VERSION 5.4 ;
NAMESCASESENSITIVE ON ;
BUSBITCHARS "[]" ;
DIVIDERCHAR "/" ;
UNITS
  DATABASE MICRONS 2000 ;
END UNITS
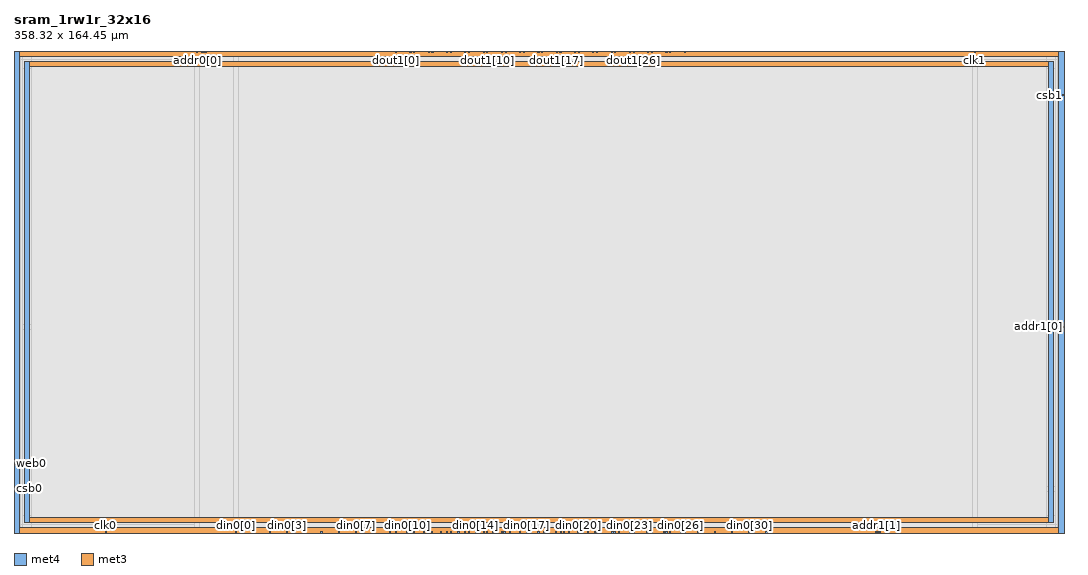
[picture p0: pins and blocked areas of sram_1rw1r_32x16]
MACRO sram_1rw1r_32x16
   CLASS BLOCK ;
   SIZE 358.32 BY 164.45 ;
   SYMMETRY X Y R90 ;
   PIN din0[0]
      DIRECTION INPUT ;
      PORT
         LAYER met4 ;
         RECT  75.56 0.0 75.94 0.38 ;
      END
   END din0[0]
   PIN din0[1]
      DIRECTION INPUT ;
      PORT
         LAYER met4 ;
         RECT  81.4 0.0 81.78 0.38 ;
      END
   END din0[1]
   PIN din0[2]
      DIRECTION INPUT ;
      PORT
         LAYER met4 ;
         RECT  87.24 0.0 87.62 0.38 ;
      END
   END din0[2]
   PIN din0[3]
      DIRECTION INPUT ;
      PORT
         LAYER met4 ;
         RECT  93.08 0.0 93.46 0.38 ;
      END
   END din0[3]
   PIN din0[4]
      DIRECTION INPUT ;
      PORT
         LAYER met4 ;
         RECT  98.92 0.0 99.3 0.38 ;
      END
   END din0[4]
   PIN din0[5]
      DIRECTION INPUT ;
      PORT
         LAYER met4 ;
         RECT  104.76 0.0 105.14 0.38 ;
      END
   END din0[5]
   PIN din0[6]
      DIRECTION INPUT ;
      PORT
         LAYER met4 ;
         RECT  110.6 0.0 110.98 0.38 ;
      END
   END din0[6]
   PIN din0[7]
      DIRECTION INPUT ;
      PORT
         LAYER met4 ;
         RECT  116.44 0.0 116.82 0.38 ;
      END
   END din0[7]
   PIN din0[8]
      DIRECTION INPUT ;
      PORT
         LAYER met4 ;
         RECT  122.28 0.0 122.66 0.38 ;
      END
   END din0[8]
   PIN din0[9]
      DIRECTION INPUT ;
      PORT
         LAYER met4 ;
         RECT  128.12 0.0 128.5 0.38 ;
      END
   END din0[9]
   PIN din0[10]
      DIRECTION INPUT ;
      PORT
         LAYER met4 ;
         RECT  133.96 0.0 134.34 0.38 ;
      END
   END din0[10]
   PIN din0[11]
      DIRECTION INPUT ;
      PORT
         LAYER met4 ;
         RECT  139.8 0.0 140.18 0.38 ;
      END
   END din0[11]
   PIN din0[12]
      DIRECTION INPUT ;
      PORT
         LAYER met4 ;
         RECT  145.64 0.0 146.02 0.38 ;
      END
   END din0[12]
   PIN din0[13]
      DIRECTION INPUT ;
      PORT
         LAYER met4 ;
         RECT  151.48 0.0 151.86 0.38 ;
      END
   END din0[13]
   PIN din0[14]
      DIRECTION INPUT ;
      PORT
         LAYER met4 ;
         RECT  157.32 0.0 157.7 0.38 ;
      END
   END din0[14]
   PIN din0[15]
      DIRECTION INPUT ;
      PORT
         LAYER met4 ;
         RECT  163.16 0.0 163.54 0.38 ;
      END
   END din0[15]
   PIN din0[16]
      DIRECTION INPUT ;
      PORT
         LAYER met4 ;
         RECT  169.0 0.0 169.38 0.38 ;
      END
   END din0[16]
   PIN din0[17]
      DIRECTION INPUT ;
      PORT
         LAYER met4 ;
         RECT  174.84 0.0 175.22 0.38 ;
      END
   END din0[17]
   PIN din0[18]
      DIRECTION INPUT ;
      PORT
         LAYER met4 ;
         RECT  180.68 0.0 181.06 0.38 ;
      END
   END din0[18]
   PIN din0[19]
      DIRECTION INPUT ;
      PORT
         LAYER met4 ;
         RECT  186.52 0.0 186.9 0.38 ;
      END
   END din0[19]
   PIN din0[20]
      DIRECTION INPUT ;
      PORT
         LAYER met4 ;
         RECT  192.36 0.0 192.74 0.38 ;
      END
   END din0[20]
   PIN din0[21]
      DIRECTION INPUT ;
      PORT
         LAYER met4 ;
         RECT  198.2 0.0 198.58 0.38 ;
      END
   END din0[21]
   PIN din0[22]
      DIRECTION INPUT ;
      PORT
         LAYER met4 ;
         RECT  204.04 0.0 204.42 0.38 ;
      END
   END din0[22]
   PIN din0[23]
      DIRECTION INPUT ;
      PORT
         LAYER met4 ;
         RECT  209.88 0.0 210.26 0.38 ;
      END
   END din0[23]
   PIN din0[24]
      DIRECTION INPUT ;
      PORT
         LAYER met4 ;
         RECT  215.72 0.0 216.1 0.38 ;
      END
   END din0[24]
   PIN din0[25]
      DIRECTION INPUT ;
      PORT
         LAYER met4 ;
         RECT  221.56 0.0 221.94 0.38 ;
      END
   END din0[25]
   PIN din0[26]
      DIRECTION INPUT ;
      PORT
         LAYER met4 ;
         RECT  227.4 0.0 227.78 0.38 ;
      END
   END din0[26]
   PIN din0[27]
      DIRECTION INPUT ;
      PORT
         LAYER met4 ;
         RECT  233.24 0.0 233.62 0.38 ;
      END
   END din0[27]
   PIN din0[28]
      DIRECTION INPUT ;
      PORT
         LAYER met4 ;
         RECT  239.08 0.0 239.46 0.38 ;
      END
   END din0[28]
   PIN din0[29]
      DIRECTION INPUT ;
      PORT
         LAYER met4 ;
         RECT  244.92 0.0 245.3 0.38 ;
      END
   END din0[29]
   PIN din0[30]
      DIRECTION INPUT ;
      PORT
         LAYER met4 ;
         RECT  250.76 0.0 251.14 0.38 ;
      END
   END din0[30]
   PIN din0[31]
      DIRECTION INPUT ;
      PORT
         LAYER met4 ;
         RECT  256.6 0.0 256.98 0.38 ;
      END
   END din0[31]
   PIN addr0[0]
      DIRECTION INPUT ;
      PORT
         LAYER met4 ;
         RECT  62.34 164.07 62.72 164.45 ;
      END
   END addr0[0]
   PIN addr0[1]
      DIRECTION INPUT ;
      PORT
         LAYER met4 ;
         RECT  65.315 164.07 65.695 164.45 ;
      END
   END addr0[1]
   PIN addr0[2]
      DIRECTION INPUT ;
      PORT
         LAYER met4 ;
         RECT  64.625 164.07 65.005 164.45 ;
      END
   END addr0[2]
   PIN addr0[3]
      DIRECTION INPUT ;
      PORT
         LAYER met4 ;
         RECT  63.88 164.07 64.26 164.45 ;
      END
   END addr0[3]
   PIN addr1[0]
      DIRECTION INPUT ;
      PORT
         LAYER met3 ;
         RECT  357.94 70.215 358.32 70.595 ;
      END
   END addr1[0]
   PIN addr1[1]
      DIRECTION INPUT ;
      PORT
         LAYER met4 ;
         RECT  294.005 0.0 294.385 0.38 ;
      END
   END addr1[1]
   PIN addr1[2]
      DIRECTION INPUT ;
      PORT
         LAYER met4 ;
         RECT  294.695 0.0 295.075 0.38 ;
      END
   END addr1[2]
   PIN addr1[3]
      DIRECTION INPUT ;
      PORT
         LAYER met4 ;
         RECT  295.44 0.0 295.82 0.38 ;
      END
   END addr1[3]
   PIN csb0
      DIRECTION INPUT ;
      PORT
         LAYER met3 ;
         RECT  0.0 14.87 0.38 15.25 ;
      END
   END csb0
   PIN csb1
      DIRECTION INPUT ;
      PORT
         LAYER met3 ;
         RECT  357.94 149.2 358.32 149.58 ;
      END
   END csb1
   PIN web0
      DIRECTION INPUT ;
      PORT
         LAYER met3 ;
         RECT  0.0 23.37 0.38 23.75 ;
      END
   END web0
   PIN clk0
      DIRECTION INPUT ;
      PORT
         LAYER met4 ;
         RECT  31.1 0.0 31.48 0.38 ;
      END
   END clk0
   PIN clk1
      DIRECTION INPUT ;
      PORT
         LAYER met4 ;
         RECT  327.68 164.07 328.06 164.45 ;
      END
   END clk1
   PIN dout0[0]
      DIRECTION OUTPUT ;
      PORT
         LAYER met4 ;
         RECT  130.105 0.0 130.485 0.38 ;
      END
   END dout0[0]
   PIN dout0[1]
      DIRECTION OUTPUT ;
      PORT
         LAYER met4 ;
         RECT  135.135 0.0 135.515 0.38 ;
      END
   END dout0[1]
   PIN dout0[2]
      DIRECTION OUTPUT ;
      PORT
         LAYER met4 ;
         RECT  136.345 0.0 136.725 0.38 ;
      END
   END dout0[2]
   PIN dout0[3]
      DIRECTION OUTPUT ;
      PORT
         LAYER met4 ;
         RECT  141.375 0.0 141.755 0.38 ;
      END
   END dout0[3]
   PIN dout0[4]
      DIRECTION OUTPUT ;
      PORT
         LAYER met4 ;
         RECT  142.585 0.0 142.965 0.38 ;
      END
   END dout0[4]
   PIN dout0[5]
      DIRECTION OUTPUT ;
      PORT
         LAYER met4 ;
         RECT  147.615 0.0 147.995 0.38 ;
      END
   END dout0[5]
   PIN dout0[6]
      DIRECTION OUTPUT ;
      PORT
         LAYER met4 ;
         RECT  148.825 0.0 149.205 0.38 ;
      END
   END dout0[6]
   PIN dout0[7]
      DIRECTION OUTPUT ;
      PORT
         LAYER met4 ;
         RECT  153.855 0.0 154.235 0.38 ;
      END
   END dout0[7]
   PIN dout0[8]
      DIRECTION OUTPUT ;
      PORT
         LAYER met4 ;
         RECT  155.065 0.0 155.445 0.38 ;
      END
   END dout0[8]
   PIN dout0[9]
      DIRECTION OUTPUT ;
      PORT
         LAYER met4 ;
         RECT  160.095 0.0 160.475 0.38 ;
      END
   END dout0[9]
   PIN dout0[10]
      DIRECTION OUTPUT ;
      PORT
         LAYER met4 ;
         RECT  161.305 0.0 161.685 0.38 ;
      END
   END dout0[10]
   PIN dout0[11]
      DIRECTION OUTPUT ;
      PORT
         LAYER met4 ;
         RECT  166.335 0.0 166.715 0.38 ;
      END
   END dout0[11]
   PIN dout0[12]
      DIRECTION OUTPUT ;
      PORT
         LAYER met4 ;
         RECT  167.195 0.0 167.575 0.38 ;
      END
   END dout0[12]
   PIN dout0[13]
      DIRECTION OUTPUT ;
      PORT
         LAYER met4 ;
         RECT  172.575 0.0 172.955 0.38 ;
      END
   END dout0[13]
   PIN dout0[14]
      DIRECTION OUTPUT ;
      PORT
         LAYER met4 ;
         RECT  175.53 0.0 175.91 0.38 ;
      END
   END dout0[14]
   PIN dout0[15]
      DIRECTION OUTPUT ;
      PORT
         LAYER met4 ;
         RECT  178.815 0.0 179.195 0.38 ;
      END
   END dout0[15]
   PIN dout0[16]
      DIRECTION OUTPUT ;
      PORT
         LAYER met4 ;
         RECT  181.405 0.0 181.785 0.38 ;
      END
   END dout0[16]
   PIN dout0[17]
      DIRECTION OUTPUT ;
      PORT
         LAYER met4 ;
         RECT  184.715 0.0 185.095 0.38 ;
      END
   END dout0[17]
   PIN dout0[18]
      DIRECTION OUTPUT ;
      PORT
         LAYER met4 ;
         RECT  187.645 0.0 188.025 0.38 ;
      END
   END dout0[18]
   PIN dout0[19]
      DIRECTION OUTPUT ;
      PORT
         LAYER met4 ;
         RECT  189.355 0.0 189.735 0.38 ;
      END
   END dout0[19]
   PIN dout0[20]
      DIRECTION OUTPUT ;
      PORT
         LAYER met4 ;
         RECT  193.05 0.0 193.43 0.38 ;
      END
   END dout0[20]
   PIN dout0[21]
      DIRECTION OUTPUT ;
      PORT
         LAYER met4 ;
         RECT  195.595 0.0 195.975 0.38 ;
      END
   END dout0[21]
   PIN dout0[22]
      DIRECTION OUTPUT ;
      PORT
         LAYER met4 ;
         RECT  198.89 0.0 199.27 0.38 ;
      END
   END dout0[22]
   PIN dout0[23]
      DIRECTION OUTPUT ;
      PORT
         LAYER met4 ;
         RECT  204.73 0.0 205.11 0.38 ;
      END
   END dout0[23]
   PIN dout0[24]
      DIRECTION OUTPUT ;
      PORT
         LAYER met4 ;
         RECT  206.365 0.0 206.745 0.38 ;
      END
   END dout0[24]
   PIN dout0[25]
      DIRECTION OUTPUT ;
      PORT
         LAYER met4 ;
         RECT  210.57 0.0 210.95 0.38 ;
      END
   END dout0[25]
   PIN dout0[26]
      DIRECTION OUTPUT ;
      PORT
         LAYER met4 ;
         RECT  211.285 0.0 211.665 0.38 ;
      END
   END dout0[26]
   PIN dout0[27]
      DIRECTION OUTPUT ;
      PORT
         LAYER met4 ;
         RECT  216.41 0.0 216.79 0.38 ;
      END
   END dout0[27]
   PIN dout0[28]
      DIRECTION OUTPUT ;
      PORT
         LAYER met4 ;
         RECT  217.465 0.0 217.845 0.38 ;
      END
   END dout0[28]
   PIN dout0[29]
      DIRECTION OUTPUT ;
      PORT
         LAYER met4 ;
         RECT  222.495 0.0 222.875 0.38 ;
      END
   END dout0[29]
   PIN dout0[30]
      DIRECTION OUTPUT ;
      PORT
         LAYER met4 ;
         RECT  223.705 0.0 224.085 0.38 ;
      END
   END dout0[30]
   PIN dout0[31]
      DIRECTION OUTPUT ;
      PORT
         LAYER met4 ;
         RECT  228.735 0.0 229.115 0.38 ;
      END
   END dout0[31]
   PIN dout1[0]
      DIRECTION OUTPUT ;
      PORT
         LAYER met4 ;
         RECT  130.165 164.07 130.545 164.45 ;
      END
   END dout1[0]
   PIN dout1[1]
      DIRECTION OUTPUT ;
      PORT
         LAYER met4 ;
         RECT  135.135 164.07 135.515 164.45 ;
      END
   END dout1[1]
   PIN dout1[2]
      DIRECTION OUTPUT ;
      PORT
         LAYER met4 ;
         RECT  136.405 164.07 136.785 164.45 ;
      END
   END dout1[2]
   PIN dout1[3]
      DIRECTION OUTPUT ;
      PORT
         LAYER met4 ;
         RECT  141.375 164.07 141.755 164.45 ;
      END
   END dout1[3]
   PIN dout1[4]
      DIRECTION OUTPUT ;
      PORT
         LAYER met4 ;
         RECT  142.645 164.07 143.025 164.45 ;
      END
   END dout1[4]
   PIN dout1[5]
      DIRECTION OUTPUT ;
      PORT
         LAYER met4 ;
         RECT  147.615 164.07 147.995 164.45 ;
      END
   END dout1[5]
   PIN dout1[6]
      DIRECTION OUTPUT ;
      PORT
         LAYER met4 ;
         RECT  148.885 164.07 149.265 164.45 ;
      END
   END dout1[6]
   PIN dout1[7]
      DIRECTION OUTPUT ;
      PORT
         LAYER met4 ;
         RECT  153.855 164.07 154.235 164.45 ;
      END
   END dout1[7]
   PIN dout1[8]
      DIRECTION OUTPUT ;
      PORT
         LAYER met4 ;
         RECT  155.125 164.07 155.505 164.45 ;
      END
   END dout1[8]
   PIN dout1[9]
      DIRECTION OUTPUT ;
      PORT
         LAYER met4 ;
         RECT  160.095 164.07 160.475 164.45 ;
      END
   END dout1[9]
   PIN dout1[10]
      DIRECTION OUTPUT ;
      PORT
         LAYER met4 ;
         RECT  161.365 164.07 161.745 164.45 ;
      END
   END dout1[10]
   PIN dout1[11]
      DIRECTION OUTPUT ;
      PORT
         LAYER met4 ;
         RECT  166.335 164.07 166.715 164.45 ;
      END
   END dout1[11]
   PIN dout1[12]
      DIRECTION OUTPUT ;
      PORT
         LAYER met4 ;
         RECT  167.605 164.07 167.985 164.45 ;
      END
   END dout1[12]
   PIN dout1[13]
      DIRECTION OUTPUT ;
      PORT
         LAYER met4 ;
         RECT  172.575 164.07 172.955 164.45 ;
      END
   END dout1[13]
   PIN dout1[14]
      DIRECTION OUTPUT ;
      PORT
         LAYER met4 ;
         RECT  173.845 164.07 174.225 164.45 ;
      END
   END dout1[14]
   PIN dout1[15]
      DIRECTION OUTPUT ;
      PORT
         LAYER met4 ;
         RECT  178.815 164.07 179.195 164.45 ;
      END
   END dout1[15]
   PIN dout1[16]
      DIRECTION OUTPUT ;
      PORT
         LAYER met4 ;
         RECT  180.085 164.07 180.465 164.45 ;
      END
   END dout1[16]
   PIN dout1[17]
      DIRECTION OUTPUT ;
      PORT
         LAYER met4 ;
         RECT  185.055 164.07 185.435 164.45 ;
      END
   END dout1[17]
   PIN dout1[18]
      DIRECTION OUTPUT ;
      PORT
         LAYER met4 ;
         RECT  186.325 164.07 186.705 164.45 ;
      END
   END dout1[18]
   PIN dout1[19]
      DIRECTION OUTPUT ;
      PORT
         LAYER met4 ;
         RECT  191.295 164.07 191.675 164.45 ;
      END
   END dout1[19]
   PIN dout1[20]
      DIRECTION OUTPUT ;
      PORT
         LAYER met4 ;
         RECT  192.565 164.07 192.945 164.45 ;
      END
   END dout1[20]
   PIN dout1[21]
      DIRECTION OUTPUT ;
      PORT
         LAYER met4 ;
         RECT  197.535 164.07 197.915 164.45 ;
      END
   END dout1[21]
   PIN dout1[22]
      DIRECTION OUTPUT ;
      PORT
         LAYER met4 ;
         RECT  198.805 164.07 199.185 164.45 ;
      END
   END dout1[22]
   PIN dout1[23]
      DIRECTION OUTPUT ;
      PORT
         LAYER met4 ;
         RECT  203.775 164.07 204.155 164.45 ;
      END
   END dout1[23]
   PIN dout1[24]
      DIRECTION OUTPUT ;
      PORT
         LAYER met4 ;
         RECT  205.045 164.07 205.425 164.45 ;
      END
   END dout1[24]
   PIN dout1[25]
      DIRECTION OUTPUT ;
      PORT
         LAYER met4 ;
         RECT  210.015 164.07 210.395 164.45 ;
      END
   END dout1[25]
   PIN dout1[26]
      DIRECTION OUTPUT ;
      PORT
         LAYER met4 ;
         RECT  211.285 164.07 211.665 164.45 ;
      END
   END dout1[26]
   PIN dout1[27]
      DIRECTION OUTPUT ;
      PORT
         LAYER met4 ;
         RECT  216.255 164.07 216.635 164.45 ;
      END
   END dout1[27]
   PIN dout1[28]
      DIRECTION OUTPUT ;
      PORT
         LAYER met4 ;
         RECT  217.525 164.07 217.905 164.45 ;
      END
   END dout1[28]
   PIN dout1[29]
      DIRECTION OUTPUT ;
      PORT
         LAYER met4 ;
         RECT  222.495 164.07 222.875 164.45 ;
      END
   END dout1[29]
   PIN dout1[30]
      DIRECTION OUTPUT ;
      PORT
         LAYER met4 ;
         RECT  223.765 164.07 224.145 164.45 ;
      END
   END dout1[30]
   PIN dout1[31]
      DIRECTION OUTPUT ;
      PORT
         LAYER met4 ;
         RECT  228.735 164.07 229.115 164.45 ;
      END
   END dout1[31]
   PIN vccd1
      DIRECTION INOUT ;
      USE POWER ; 
      SHAPE ABUTMENT ; 
      PORT
         LAYER met4 ;
         RECT  356.58 0.0 358.32 164.45 ;
         LAYER met4 ;
         RECT  0.0 0.0 1.74 164.45 ;
         LAYER met3 ;
         RECT  0.0 162.71 358.32 164.45 ;
         LAYER met3 ;
         RECT  0.0 0.0 358.32 1.74 ;
      END
   END vccd1
   PIN vssd1
      DIRECTION INOUT ;
      USE GROUND ; 
      SHAPE ABUTMENT ; 
      PORT
         LAYER met4 ;
         RECT  353.1 3.48 354.84 160.97 ;
         LAYER met3 ;
         RECT  3.48 3.48 354.84 5.22 ;
         LAYER met3 ;
         RECT  3.48 159.23 354.84 160.97 ;
         LAYER met4 ;
         RECT  3.48 3.48 5.22 160.97 ;
      END
   END vssd1
   OBS
   LAYER  met1 ;
      RECT  0.62 0.62 357.7 163.83 ;
   LAYER  met2 ;
      RECT  0.62 0.62 357.7 163.83 ;
   LAYER  met3 ;
      RECT  0.62 69.615 357.34 71.195 ;
      RECT  0.98 14.27 357.34 15.85 ;
      RECT  0.98 15.85 357.34 69.615 ;
      RECT  357.34 71.195 357.7 148.6 ;
      RECT  0.62 15.85 0.98 22.77 ;
      RECT  0.62 24.35 0.98 69.615 ;
      RECT  357.34 150.18 357.7 162.11 ;
      RECT  357.34 2.34 357.7 69.615 ;
      RECT  0.62 2.34 0.98 14.27 ;
      RECT  0.98 2.34 2.88 2.88 ;
      RECT  0.98 2.88 2.88 5.82 ;
      RECT  0.98 5.82 2.88 14.27 ;
      RECT  2.88 2.34 355.44 2.88 ;
      RECT  2.88 5.82 355.44 14.27 ;
      RECT  355.44 2.34 357.34 2.88 ;
      RECT  355.44 2.88 357.34 5.82 ;
      RECT  355.44 5.82 357.34 14.27 ;
      RECT  0.62 71.195 2.88 158.63 ;
      RECT  0.62 158.63 2.88 161.57 ;
      RECT  0.62 161.57 2.88 162.11 ;
      RECT  2.88 71.195 355.44 158.63 ;
      RECT  2.88 161.57 355.44 162.11 ;
      RECT  355.44 71.195 357.34 158.63 ;
      RECT  355.44 158.63 357.34 161.57 ;
      RECT  355.44 161.57 357.34 162.11 ;
   LAYER  met4 ;
      RECT  74.96 0.98 76.54 163.83 ;
      RECT  76.54 0.62 80.8 0.98 ;
      RECT  82.38 0.62 86.64 0.98 ;
      RECT  88.22 0.62 92.48 0.98 ;
      RECT  94.06 0.62 98.32 0.98 ;
      RECT  99.9 0.62 104.16 0.98 ;
      RECT  105.74 0.62 110.0 0.98 ;
      RECT  111.58 0.62 115.84 0.98 ;
      RECT  117.42 0.62 121.68 0.98 ;
      RECT  123.26 0.62 127.52 0.98 ;
      RECT  234.22 0.62 238.48 0.98 ;
      RECT  240.06 0.62 244.32 0.98 ;
      RECT  245.9 0.62 250.16 0.98 ;
      RECT  251.74 0.62 256.0 0.98 ;
      RECT  61.74 0.98 63.32 163.47 ;
      RECT  63.32 0.98 74.96 163.47 ;
      RECT  66.295 163.47 74.96 163.83 ;
      RECT  257.58 0.62 293.405 0.98 ;
      RECT  32.08 0.62 74.96 0.98 ;
      RECT  76.54 0.98 327.08 163.47 ;
      RECT  327.08 0.98 328.66 163.47 ;
      RECT  129.1 0.62 129.505 0.98 ;
      RECT  131.085 0.62 133.36 0.98 ;
      RECT  137.325 0.62 139.2 0.98 ;
      RECT  143.565 0.62 145.04 0.98 ;
      RECT  146.62 0.62 147.015 0.98 ;
      RECT  149.805 0.62 150.88 0.98 ;
      RECT  152.46 0.62 153.255 0.98 ;
      RECT  156.045 0.62 156.72 0.98 ;
      RECT  158.3 0.62 159.495 0.98 ;
      RECT  162.285 0.62 162.56 0.98 ;
      RECT  164.14 0.62 165.735 0.98 ;
      RECT  168.175 0.62 168.4 0.98 ;
      RECT  169.98 0.62 171.975 0.98 ;
      RECT  173.555 0.62 174.24 0.98 ;
      RECT  176.51 0.62 178.215 0.98 ;
      RECT  179.795 0.62 180.08 0.98 ;
      RECT  182.385 0.62 184.115 0.98 ;
      RECT  185.695 0.62 185.92 0.98 ;
      RECT  188.625 0.62 188.755 0.98 ;
      RECT  190.335 0.62 191.76 0.98 ;
      RECT  194.03 0.62 194.995 0.98 ;
      RECT  196.575 0.62 197.6 0.98 ;
      RECT  199.87 0.62 203.44 0.98 ;
      RECT  205.71 0.62 205.765 0.98 ;
      RECT  207.345 0.62 209.28 0.98 ;
      RECT  212.265 0.62 215.12 0.98 ;
      RECT  218.445 0.62 220.96 0.98 ;
      RECT  224.685 0.62 226.8 0.98 ;
      RECT  229.715 0.62 232.64 0.98 ;
      RECT  76.54 163.47 129.565 163.83 ;
      RECT  131.145 163.47 134.535 163.83 ;
      RECT  137.385 163.47 140.775 163.83 ;
      RECT  143.625 163.47 147.015 163.83 ;
      RECT  149.865 163.47 153.255 163.83 ;
      RECT  156.105 163.47 159.495 163.83 ;
      RECT  162.345 163.47 165.735 163.83 ;
      RECT  168.585 163.47 171.975 163.83 ;
      RECT  174.825 163.47 178.215 163.83 ;
      RECT  181.065 163.47 184.455 163.83 ;
      RECT  187.305 163.47 190.695 163.83 ;
      RECT  193.545 163.47 196.935 163.83 ;
      RECT  199.785 163.47 203.175 163.83 ;
      RECT  206.025 163.47 209.415 163.83 ;
      RECT  212.265 163.47 215.655 163.83 ;
      RECT  218.505 163.47 221.895 163.83 ;
      RECT  224.745 163.47 228.135 163.83 ;
      RECT  229.715 163.47 327.08 163.83 ;
      RECT  296.42 0.62 355.98 0.98 ;
      RECT  328.66 163.47 355.98 163.83 ;
      RECT  2.34 163.47 61.74 163.83 ;
      RECT  2.34 0.62 30.5 0.98 ;
      RECT  328.66 0.98 352.5 2.88 ;
      RECT  328.66 2.88 352.5 161.57 ;
      RECT  328.66 161.57 352.5 163.47 ;
      RECT  352.5 0.98 355.44 2.88 ;
      RECT  352.5 161.57 355.44 163.47 ;
      RECT  355.44 0.98 355.98 2.88 ;
      RECT  355.44 2.88 355.98 161.57 ;
      RECT  355.44 161.57 355.98 163.47 ;
      RECT  2.34 0.98 2.88 2.88 ;
      RECT  2.34 2.88 2.88 161.57 ;
      RECT  2.34 161.57 2.88 163.47 ;
      RECT  2.88 0.98 5.82 2.88 ;
      RECT  2.88 161.57 5.82 163.47 ;
      RECT  5.82 0.98 61.74 2.88 ;
      RECT  5.82 2.88 61.74 161.57 ;
      RECT  5.82 161.57 61.74 163.47 ;
   END
END    sram_1rw1r_32x16
END    LIBRARY
